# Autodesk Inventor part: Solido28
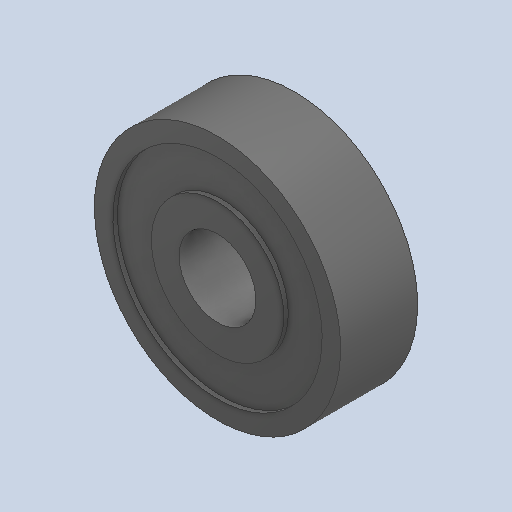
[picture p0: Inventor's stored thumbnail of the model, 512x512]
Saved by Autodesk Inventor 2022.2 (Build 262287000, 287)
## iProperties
Created: 2024-10
Part Number: Solido28
Material: Generico
Document SubType Name: Modeling
Designer: 18907419
Density: 1 g/cm^3
Appearance: Default
Author: 18907419
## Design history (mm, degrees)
feature "Solido28"
node "Solido1"
